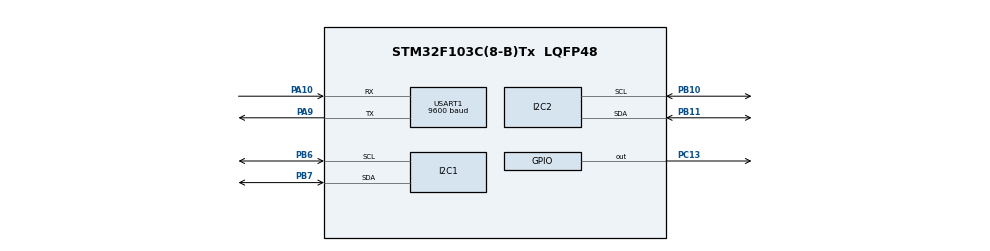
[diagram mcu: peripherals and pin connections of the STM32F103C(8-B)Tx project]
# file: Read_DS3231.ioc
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Mcu.Family=STM32F1
Mcu.Name=STM32F103C(8-B)Tx
Mcu.Package=LQFP48
NVIC.I2C1_ER_IRQn=true\:0\:0\:false\:false\:true\:true\:true
NVIC.I2C1_EV_IRQn=true\:0\:0\:false\:false\:true\:true\:true
NVIC.I2C2_ER_IRQn=true\:0\:0\:false\:false\:true\:true\:true
NVIC.I2C2_EV_IRQn=true\:0\:0\:false\:false\:true\:true\:true
NVIC.PriorityGroup=NVIC_PRIORITYGROUP_4
NVIC.USART1_IRQn=true\:0\:0\:false\:false\:true\:true\:true
PA10.Mode=Asynchronous
PA10.Signal=USART1_RX
PA13.Mode=Serial_Wire
PA13.Signal=SYS_JTMS-SWDIO
PA14.Mode=Serial_Wire
PA14.Signal=SYS_JTCK-SWCLK
PA9.Mode=Asynchronous
PA9.Signal=USART1_TX
PB10.Mode=I2C
PB10.Signal=I2C2_SCL
PB11.Mode=I2C
PB11.Signal=I2C2_SDA
PB6.Mode=I2C
PB6.Signal=I2C1_SCL
PB7.Mode=I2C
PB7.Signal=I2C1_SDA
PC13-TAMPER-RTC.Signal=GPIO_Output
ProjectManager.HeapSize=0x200
ProjectManager.StackSize=0x400
ProjectManager.TargetToolchain=MDK-ARM V5.27
RCC.APB1Freq_Value=8000000
RCC.APB2Freq_Value=8000000
USART1.BaudRate=9600
USART1.VirtualMode=VM_ASYNC
board=custom

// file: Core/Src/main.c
/* USER CODE BEGIN Header */
/**
  ******************************************************************************
  * @file           : main.c
  * @brief          : Main program body
  ******************************************************************************
  * @attention
  *
  * <h2><center>&copy; Copyright (c) 2020 STMicroelectronics.
  * All rights reserved.</center></h2>
  *
  * This software component is licensed by ST under BSD 3-Clause license,
  * the "License"; You may not use this file except in compliance with the
  * License. You may obtain a copy of the License at:
  *                        opensource.org/licenses/BSD-3-Clause
  *
  ******************************************************************************
  */
/* USER CODE END Header */
#include "main.h"

/* USER CODE BEGIN Includes */
#include "stdio.h"
#include "stm32_ds3231.h"
#include "max_matrix_stm32.h"
/* USER CODE END Includes */

I2C_HandleTypeDef hi2c1;
I2C_HandleTypeDef hi2c2;

UART_HandleTypeDef huart1;

void SystemClock_Config(void);
static void MX_GPIO_Init(void);
static void MX_I2C1_Init(void);
static void MX_USART1_UART_Init(void);
static void MX_I2C2_Init(void);

/* USER CODE BEGIN 0 */
_RTC rtc = {
    .Year = 20, .Month = 12, .Date = 16,
    .DaysOfWeek = THURSDAY,
    .Hour = 15, .Min = 04, .Sec = 00
};

uint8_t regVal;
float rtcTemp;

uint8_t split_2_backnumber(uint8_t n){
	return n%10;
}

uint8_t split_2_frontnumber(uint8_t n){
	return n/10;
}

uint8_t convert_font_num_max(uint8_t n){
	uint8_t tmp;
	switch (n){
		case 0:
			tmp = 48;
			break;
		case 1:
			 tmp = 49;
			break;
		case 2:
			tmp = 50;
			break;
		case 3:
			tmp = 51;
			break;
		case 4:
			tmp = 52;
			break;
		case 5:
			tmp = 53;
			break;
		case 6:
			tmp = 54;
			break;
		case 7:
			tmp = 55;
			break;
		case 8:
			tmp = 56;
			break;
		case 9:
			tmp = 57;
			break;
	}
	return tmp;
}
void write_rtc_max(_RTC rtc){
	uint8_t H_a, H_b, M_a, M_b, S_a, S_b;
	H_a = split_2_frontnumber(rtc.Hour);
	H_b = split_2_backnumber(rtc.Hour);
	M_a = split_2_frontnumber(rtc.Min);
	M_b = split_2_backnumber(rtc.Min);
	S_a = split_2_frontnumber(rtc.Sec);
	S_b = split_2_backnumber(rtc.Sec);

	write_char(convert_font_num_max(H_a), 4);
	write_char(convert_font_num_max(H_b), 3);
	write_char(convert_font_num_max(M_a), 2);
	write_char(convert_font_num_max(M_b), 1);

	write_char(convert_font_num_max(S_a), 7);
	write_char(convert_font_num_max(S_b), 6);

}
void max_off (){
		write_char(0, 1);
		write_char(0, 2);
		write_char(0, 3);
		write_char(0, 4);
		write_char(0, 5);
		write_char(0, 6);
		write_char(0, 7);
		write_char(0, 8);
}
void write_rtc_max_date(_RTC rtc){
	uint8_t D_a, D_b, Mo_a, Mo_b, Y_a, Y_b;

	D_a = split_2_frontnumber(rtc.Date);
	D_b = split_2_backnumber(rtc.Date);
	Mo_a = split_2_frontnumber(rtc.Month);
	Mo_b = split_2_backnumber(rtc.Month);
	Y_a = split_2_frontnumber(rtc.Year);
	Y_b = split_2_backnumber(rtc.Year);

	write_char(convert_font_num_max(D_a), 4);
	write_char(convert_font_num_max(D_b), 3);

	write_char(convert_font_num_max(Mo_a), 2);
	write_char(convert_font_num_max(Mo_b), 1);

	write_char(convert_font_num_max(Y_a), 7);
	write_char(convert_font_num_max(Y_b), 6);

}
/* USER CODE END 0 */

int main(void)
{

  /* MCU Configuration--------------------------------------------------------*/

  /* Reset of all peripherals, Initializes the Flash interface and the Systick. */
  HAL_Init();

  /* Configure the system clock */
  SystemClock_Config();

  /* Initialize all configured peripherals */
  MX_GPIO_Init();
  MX_I2C1_Init();
  MX_USART1_UART_Init();
  MX_I2C2_Init();
  /* USER CODE BEGIN 2 */
	// Init port i2c and set time
	DS3231_Init(&hi2c1);
  DS3231_SetTime(&rtc);
	max_init (0x0f);

//	//scan bus i2c to check connect
	char uart2Data[24] = "Connected to UART Two\r\n";
   /*
    * Output to uart2
    * use screen or putty or whatever terminal software
    * 8N1 115200
    */
  HAL_UART_Transmit(&huart1, (uint8_t *)&uart2Data,sizeof(uart2Data), 0xFFFF);

 	printf("\r\n");

 	printf("Scanning I2C bus:\r\n");
	HAL_StatusTypeDef result;
 	uint8_t i;
 	for (i=1; i<128; i++)
 	{
 	  /*
 	   * the HAL wants a left aligned i2c address
 	   * &hi2c1 is the handle
 	   * (uint16_t)(i<<1) is the i2c address left aligned
 	   * retries 2
 	   * timeout 2
 	   */
 	  result = HAL_I2C_IsDeviceReady(&hi2c1, (uint16_t)(i<<1), 2, 2);
 	  if (result != HAL_OK) // HAL_ERROR or HAL_BUSY or HAL_TIMEOUT
 	  {
 		  printf("."); // No ACK received at that address
 	  }
 	  if (result == HAL_OK)
 	  {
 		  printf("0x%X", i); // Received an ACK at that address
 	  }
 	}
 	printf("\r\n");

  /* USER CODE END 2 */

  /* Infinite loop */
 while (1)
  {

    /* USER CODE BEGIN 3 */
		//get time
		DS3231_GetTime(&rtc);
    DS3231_ReadTemperature(&rtcTemp);

		ReadRegister(DS3231_REG_STATUS, &regVal);
    if(regVal & DS3231_STA_A1F)
    {
      regVal &= ~DS3231_STA_A1F;
      WriteRegister(DS3231_REG_STATUS, regVal);
    }
		if(rtc.Sec==39){
			max_clear();
			write_rtc_max_date(rtc);
			HAL_Delay(5000);
			max_clear();

		}
		else if (rtc.Min %5 == 0){
			max_clear();
			scroll_string((uint8_t *) "Nguyen Thien Dat   ", 5, left);
			HAL_Delay(1000);
			max_clear();
		}
		else {
			write_rtc_max(rtc);
		}

  }
  /* USER CODE END 3 */
}

void SystemClock_Config(void)
{
  RCC_OscInitTypeDef RCC_OscInitStruct = {0};
  RCC_ClkInitTypeDef RCC_ClkInitStruct = {0};

  /** Initializes the RCC Oscillators according to the specified parameters
  * in the RCC_OscInitTypeDef structure.
  */
  RCC_OscInitStruct.OscillatorType = RCC_OSCILLATORTYPE_HSI;
  RCC_OscInitStruct.HSIState = RCC_HSI_ON;
  RCC_OscInitStruct.HSICalibrationValue = RCC_HSICALIBRATION_DEFAULT;
  RCC_OscInitStruct.PLL.PLLState = RCC_PLL_NONE;
  if (HAL_RCC_OscConfig(&RCC_OscInitStruct) != HAL_OK)
  {
    Error_Handler();
  }
  /** Initializes the CPU, AHB and APB buses clocks
  */
  RCC_ClkInitStruct.ClockType = RCC_CLOCKTYPE_HCLK|RCC_CLOCKTYPE_SYSCLK
                              |RCC_CLOCKTYPE_PCLK1|RCC_CLOCKTYPE_PCLK2;
  RCC_ClkInitStruct.SYSCLKSource = RCC_SYSCLKSOURCE_HSI;
  RCC_ClkInitStruct.AHBCLKDivider = RCC_SYSCLK_DIV1;
  RCC_ClkInitStruct.APB1CLKDivider = RCC_HCLK_DIV1;
  RCC_ClkInitStruct.APB2CLKDivider = RCC_HCLK_DIV1;

  if (HAL_RCC_ClockConfig(&RCC_ClkInitStruct, FLASH_LATENCY_0) != HAL_OK)
  {
    Error_Handler();
  }
}

static void MX_I2C1_Init(void)
{

  hi2c1.Instance = I2C1;
  hi2c1.Init.ClockSpeed = 100000;
  hi2c1.Init.DutyCycle = I2C_DUTYCYCLE_2;
  hi2c1.Init.OwnAddress1 = 0;
  hi2c1.Init.AddressingMode = I2C_ADDRESSINGMODE_7BIT;
  hi2c1.Init.DualAddressMode = I2C_DUALADDRESS_DISABLE;
  hi2c1.Init.OwnAddress2 = 0;
  hi2c1.Init.GeneralCallMode = I2C_GENERALCALL_DISABLE;
  hi2c1.Init.NoStretchMode = I2C_NOSTRETCH_DISABLE;
  if (HAL_I2C_Init(&hi2c1) != HAL_OK)
  {
    Error_Handler();
  }

}

static void MX_I2C2_Init(void)
{

  hi2c2.Instance = I2C2;
  hi2c2.Init.ClockSpeed = 100000;
  hi2c2.Init.DutyCycle = I2C_DUTYCYCLE_2;
  hi2c2.Init.OwnAddress1 = 0;
  hi2c2.Init.AddressingMode = I2C_ADDRESSINGMODE_7BIT;
  hi2c2.Init.DualAddressMode = I2C_DUALADDRESS_DISABLE;
  hi2c2.Init.OwnAddress2 = 0;
  hi2c2.Init.GeneralCallMode = I2C_GENERALCALL_DISABLE;
  hi2c2.Init.NoStretchMode = I2C_NOSTRETCH_DISABLE;
  if (HAL_I2C_Init(&hi2c2) != HAL_OK)
  {
    Error_Handler();
  }

}

static void MX_USART1_UART_Init(void)
{

  huart1.Instance = USART1;
  huart1.Init.BaudRate = 9600;
  huart1.Init.WordLength = UART_WORDLENGTH_8B;
  huart1.Init.StopBits = UART_STOPBITS_1;
  huart1.Init.Parity = UART_PARITY_NONE;
  huart1.Init.Mode = UART_MODE_TX_RX;
  huart1.Init.HwFlowCtl = UART_HWCONTROL_NONE;
  huart1.Init.OverSampling = UART_OVERSAMPLING_16;
  if (HAL_UART_Init(&huart1) != HAL_OK)
  {
    Error_Handler();
  }

}

static void MX_GPIO_Init(void)
{
  GPIO_InitTypeDef GPIO_InitStruct = {0};

  /* GPIO Ports Clock Enable */
  __HAL_RCC_GPIOC_CLK_ENABLE();
  __HAL_RCC_GPIOA_CLK_ENABLE();
  __HAL_RCC_GPIOB_CLK_ENABLE();

  /*Configure GPIO pin Output Level */
  HAL_GPIO_WritePin(GPIOC, GPIO_PIN_13, GPIO_PIN_RESET);

  /*Configure GPIO pin Output Level */
  HAL_GPIO_WritePin(GPIOA, GPIO_PIN_2|GPIO_PIN_3|GPIO_PIN_4, GPIO_PIN_RESET);

  /*Configure GPIO pin : PC13 */
  GPIO_InitStruct.Pin = GPIO_PIN_13;
  GPIO_InitStruct.Mode = GPIO_MODE_OUTPUT_PP;
  GPIO_InitStruct.Pull = GPIO_NOPULL;
  GPIO_InitStruct.Speed = GPIO_SPEED_FREQ_LOW;
  HAL_GPIO_Init(GPIOC, &GPIO_InitStruct);

  /*Configure GPIO pins : PA2 PA3 PA4 */
  GPIO_InitStruct.Pin = GPIO_PIN_2|GPIO_PIN_3|GPIO_PIN_4;
  GPIO_InitStruct.Mode = GPIO_MODE_OUTPUT_PP;
  GPIO_InitStruct.Pull = GPIO_NOPULL;
  GPIO_InitStruct.Speed = GPIO_SPEED_FREQ_LOW;
  HAL_GPIO_Init(GPIOA, &GPIO_InitStruct);

}

/* USER CODE BEGIN 4 */
#ifdef __GNUC__
  /* With GCC/RAISONANCE, small printf (option LD Linker->Libraries->Small printf
     set to 'Yes') calls __io_putchar() */
  #define PUTCHAR_PROTOTYPE int __io_putchar(int ch)
#else
  #define PUTCHAR_PROTOTYPE int fputc(int ch, FILE *f)
#endif /* __GNUC__ */
/**
  * @brief  Retargets the C library printf function to the USART.
  * @param  None
  * @retval None
  */
PUTCHAR_PROTOTYPE
{
  /* Place your implementation of fputc here */
  /* e.g. write a character to the EVAL_COM1 and Loop until the end of transmission */
  HAL_UART_Transmit(&huart1, (uint8_t *)&ch, 1, 100);

  return ch;
}
/* USER CODE END 4 */

void Error_Handler(void)
{
  __disable_irq();
  while (1)
  {
  }
}

/************************ (C) COPYRIGHT STMicroelectronics *****END OF FILE****/
